VERSION 5.7 ;
  NOWIREEXTENSIONATPIN ON ;
  DIVIDERCHAR "/" ;
  BUSBITCHARS "[]" ;
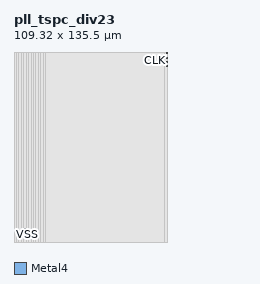
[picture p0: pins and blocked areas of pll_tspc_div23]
MACRO pll_tspc_div23
  CLASS BLOCK ;
  FOREIGN pll_tspc_div23 0.000 0.000 ;
  ORIGIN 0.000 0.000 ;
  SIZE 109.320 BY 135.500 ;
  SYMMETRY X Y ;
  PIN Q2
    DIRECTION OUTPUT ;
    USE SIGNAL ;
    ANTENNAGATEAREA 0.156000 ;
    ANTENNADIFFAREA 2.015400 ;
    PORT
      LAYER Metal4 ;
        RECT 108.700 125.190 109.320 125.810 ;
    END
  END Q2
  PIN VSS
    DIRECTION INOUT ;
    USE GROUND ;
    PORT
      LAYER Metal4 ;
        RECT 4.010 2.690 4.630 3.310 ;
    END
  END VSS
  PIN VDD
    DIRECTION INOUT ;
    USE POWER ;
    PORT
      LAYER Metal4 ;
        RECT 7.510 8.690 8.130 9.310 ;
    END
  END VDD
  PIN RESET_B
    DIRECTION INPUT ;
    USE SIGNAL ;
    ANTENNAGATEAREA 0.468000 ;
    ANTENNADIFFAREA 2.015400 ;
    PORT
      LAYER Metal4 ;
        RECT 108.700 128.190 109.320 128.810 ;
    END
  END RESET_B
  PIN CLK
    DIRECTION INPUT ;
    USE SIGNAL ;
    ANTENNAGATEAREA 1.560000 ;
    ANTENNADIFFAREA 2.015400 ;
    PORT
      LAYER Metal4 ;
        RECT 108.700 131.190 109.320 131.810 ;
    END
  END CLK
  PIN MODULUS_REQUEST
    DIRECTION INPUT ;
    USE SIGNAL ;
    ANTENNAGATEAREA 0.312000 ;
    ANTENNADIFFAREA 2.015400 ;
    PORT
      LAYER Metal4 ;
        RECT 108.700 134.190 109.320 134.810 ;
    END
  END MODULUS_REQUEST
  OBS
    LAYER Metal1 ;
      RECT 0.000 0.000 109.320 135.500 ;
    LAYER Metal2 ;
      RECT 0.000 0.000 107.320 135.500 ;
    LAYER Metal3 ;
      RECT 0.000 0.000 107.320 135.500 ;
    LAYER Metal4 ;
      RECT 0.000 0.000 107.320 135.500 ;
    LAYER TopMetal1 ;
      RECT 0.000 0.000 1.640 135.500 ;
      RECT 3.500 0.000 5.140 135.500 ;
      RECT 7.000 0.000 8.640 135.500 ;
      RECT 10.500 0.000 12.140 135.500 ;
      RECT 14.000 0.000 15.640 135.500 ;
      RECT 17.500 0.000 19.140 135.500 ;
      RECT 21.000 0.000 22.640 135.500 ;
  END
END pll_tspc_div23
END LIBRARY
